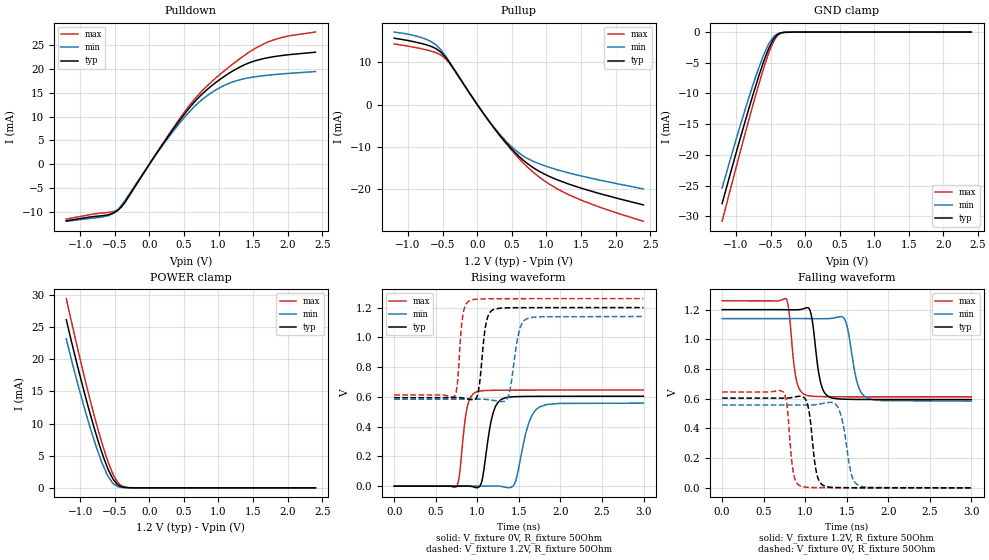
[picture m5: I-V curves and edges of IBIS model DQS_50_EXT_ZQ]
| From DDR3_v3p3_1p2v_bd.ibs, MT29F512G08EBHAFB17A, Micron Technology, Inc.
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| MODEL DQS_50_EXT_ZQ (50 Ohm Data Strobe I/O with no ODT, With ZQ Cal)
[Model]   DQS_50_EXT_ZQ
Model_type   I/O
Vinl = 450.000mV
Vinh = 750.000mV
Vmeas = 600.000mV
Vref = 600.000mV
Cref = 0.0pF
Rref = 50.000Ohm
|   typ   min   max
|C_comp   1.240pF   1.143pF   1.340pF
C_comp_pullup   0.6200pF   0.5715pF   0.6700pF
C_comp_pulldown   0.6200pF   0.5715pF   0.6700pF
[Model Spec]
| Input threshold voltage corners
Vinl   0.4500V   0.4200V   0.4800V
Vinh   0.7500V   0.7200V   0.7800V
| Measurement voltage corners
Vmeas   0.6000V   0.5700V   0.6300V
| Timing spec test load voltage corners
Vref   0.6000V   0.5700V   0.6300V
| Dynamic Overshoot Parameters from ONFI4 Specification
D_overshoot_ampl_h   0.80   NA   NA
D_overshoot_ampl_l   0.80   NA   NA
D_overshoot_area_h   0.38n   NA   NA
D_overshoot_area_l   0.38n   NA   NA
[Receiver Thresholds]
|Vth   =  0.600V
|Vth_min  =  0.5880V
|Vth_max  =  0.6120V
|Vinh_ac  =  0.150V
|Vinh_dc  =  0.100V
|Vinl_ac  = -0.150V
|Vinl_dc  = -0.100V
|Tslew_ac =  5.000ns |Not specified, so set to high value
|Threshold_sensitivity = 0.50
|Reference_supply Pullup_ref
Vcross_low   = 0.480V
Vcross_high  = 0.720V
Vdiff_ac   = 300mV
Vdiff_dc   = 200mV
Tdiffslew_ac = 10.000ns |Not specified, so set to high value
[Voltage Range]   1.2000V   1.1400V   1.2600V
[Pullup Reference]   1.2000V   1.1400V   1.2600V
| Junction Temperature (Ambient temp is 35C typ, 70C min, 0C max)
[Temperature Range]   50.0   85.0   0.0
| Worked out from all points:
|   slope of the pulldown table from 0 to 0.18 V, typ, clamps not added: 45.8 ohm
|   slope of the pullup table from 0 to 0.18 V, typ, clamps not added: 43.5 ohm
|   GND clamp passes 1 mA (typ) near -0.44 V on its own axis
|   POWER clamp passes 1 mA (typ) near -0.50 V on its own axis
|   falling waveform, V_fixture 1.2V, R_fixture 50Ohm: 20-80 % time 86ps typ, 108ps min, 73.2ps max; typ from 1.2 V to 0.594 V
|   rising waveform, V_fixture 0V, R_fixture 50Ohm: 20-80 % time 104ps typ, 140ps min, 77.8ps max; typ from 0 V to 0.604 V
|   rising waveform, V_fixture 1.2V, R_fixture 50Ohm: 20-80 % time 68.2ps typ, 90.4ps min, 52.9ps max; typ from 0.594 V to 1.2 V
|   falling waveform, V_fixture 0V, R_fixture 50Ohm: 20-80 % time 74.4ps typ, 97.1ps min, 60.8ps max; typ from 0.604 V to 0 V
[Pulldown]
|   Voltage   I(typ)   I(min)   I(max)
-1.2V     -11.9mA    -11.98mA   -11.52mA
-603.8mV  -10.66mA   -10.84mA   -10.13mA
-525.6mV  -10.31mA   -10.34mA   -9.968mA
-406.2mV  -8.981mA   -8.665mA   -8.998mA
130.4mV   2.867mA    2.72mA     2.942mA
446.2mV   9.375mA    8.794mA    9.732mA
719.8mV   14.13mA    13.06mA    14.77mA
966mV     17.24mA    15.66mA    18.2mA
1.324V    20.54mA    17.81mA    22.34mA
1.661V    22.23mA    18.62mA    25.35mA
1.997V    22.99mA    19.07mA    26.91mA
2.4V      23.54mA    19.47mA    27.77mA
[GND Clamp]
|   Voltage   I(typ)   I(min)   I(max)
-1.2V     -27.93mA   -25.37mA   -30.8mA
-976.8mV  -18.84mA   -16.69mA   -21.15mA
-838.6mV  -13.43mA   -11.57mA   -15.32mA
-681.3mV  -7.582mA   -6.181mA   -8.965mA
-603.8mV  -4.945mA   -3.844mA   -6.063mA
-525.6mV  -2.67mA    -1.913mA   -3.416mA
-460.8mV  -1.224mA   -852.9uA   -1.63mA
-447.6mV  -1.04mA    -637.3uA   -1.388mA
-406.2mV  -469uA     -373.7uA   -636.4uA
-355.8mV  -157.5uA   -119.8uA   -181.3uA
-118.9mV  -137.7nA   -5.032uA   0A
2.402V    0A         0A         0A
[Pullup]
|   Voltage   I(typ)   I(min)   I(max)
-1.2V     15.67mA    17.12mA    14.3mA
-682.4mV  13.83mA    15.02mA    12.7mA
-602.8mV  13.26mA    14.18mA    12.28mA
-461.6mV  11.28mA    11.54mA    10.86mA
-118.9mV  2.89mA     2.882mA    2.88mA
199.9mV   -4.575mA   -4.486mA   -4.619mA
456.9mV   -9.743mA   -9.33mA    -10.02mA
680.4mV   -13.32mA   -12.29mA   -14.03mA
970.6mV   -16.4mA    -14.42mA   -18mA
1.321V    -18.75mA   -16.11mA   -21.25mA
1.765V    -20.98mA   -17.8mA    -24.18mA
2.4V      -23.67mA   -19.89mA   -27.53mA
[POWER Clamp]
|   Voltage   I(typ)   I(min)   I(max)
-1.2V     26.15mA    23.18mA    29.43mA
-1.072V   20.45mA    17.71mA    23.36mA
-916.1mV  13.92mA    11.59mA    16.29mA
-796.8mV  9.308mA    7.386mA    11.27mA
-682.8mV  5.417mA    3.858mA    6.916mA
-603.8mV  3.107mA    1.935mA    4.308mA
-528mV    1.431mA    725uA      2.233mA
-461.6mV  525.6uA    247uA      933.2uA
-406.2mV  169.5uA    79.4uA     344uA
-355.8mV  81.44uA    14.39uA    117.3uA
-210.9mV  1.333uA    779.3nA    2.557uA
2.402V    0A         0A         0A
[Ramp]
R_load = 50
|   typ   min   max
dV/dt_r 3.6255E-01/1.0400E-10   3.3453E-01/1.3950E-10   3.8749E-01/7.7617E-11
dV/dt_f 3.6334E-01/8.5731E-11   3.3331E-01/1.0713E-10   3.8855E-01/7.2814E-11
[Falling Waveform]
V_fixture = 1.2V
V_fixture_min = 1.14V
V_fixture_max = 1.26V
R_fixture = 50Ohm
C_fixture = 0F
|   Time   V(typ)   V(min)   V(max)
0s        1.2V       1.14V      1.26V
776ps     1.2V       1.14V      1.269V
888ps     1.199V     1.14V      742.1mV
1.006ns   1.211V     1.14V      625.1mV
1.07ns    1.171V     1.14V      617.8mV
1.264ns   620.7mV    1.139V     613.8mV
1.472ns   597mV      1.139V     613mV
1.628ns   595.4mV    703.6mV    612.8mV
1.746ns   595mV      604.2mV    612.7mV
2.998ns   594.4mV    584.4mV    612.4mV
[Rising Waveform]
V_fixture = 0V
V_fixture_min = 0V
V_fixture_max = 0V
R_fixture = 50Ohm
C_fixture = 0F
|   Time   V(typ)   V(min)   V(max)
0s        103.7uV    217.2uV    28.95uV
748ps     212.7uV    98.54uV    -3.598mV
878ps     1.295mV    58.42uV    529.2mV
986ps     -10.23mV   40.97uV    632.6mV
1.19ns    491.8mV    1.196mV    643.9mV
1.286ns   581.6mV    -1.252mV   644.5mV
1.45ns    601.1mV    17.55mV    645.1mV
1.62ns    603.2mV    425.6mV    645.4mV
1.744ns   603.6mV    530.9mV    645.5mV
2.998ns   604.4mV    557.8mV    645.9mV
[Rising Waveform]
V_fixture = 1.2V
V_fixture_min = 1.14V
V_fixture_max = 1.26V
R_fixture = 50Ohm
C_fixture = 0F
|   Time   V(typ)   V(min)   V(max)
0s        594.4mV    584.4mV    612.4mV
724ps     594.5mV    584.2mV    601.8mV
826ps     592mV      584.1mV    1.149V
912ps     583.1mV    584.2mV    1.248V
1ns       605.7mV    584.4mV    1.256V
1.106ns   1.097V     582.8mV    1.258V
1.176ns   1.181V     577.6mV    1.259V
1.364ns   1.198V     591.9mV    1.259V
1.588ns   1.199V     1.123V     1.26V
2.998ns   1.2V       1.14V      1.26V
[Falling Waveform]
|Gnd
V_fixture = 0V
V_fixture_min = 0V
V_fixture_max = 0V
R_fixture = 50Ohm
C_fixture = 0F
|   Time   V(typ)   V(min)   V(max)
0s        604.3mV    557.7mV    645.8mV
734ps     603.9mV    557.9mV    647.2mV
858ps     610.3mV    558mV      98.93mV
944ps     617.3mV    557.6mV    11.85mV
1.028ns   560.7mV    557.2mV    3.434mV
1.122ns   142.1mV    559.8mV    1.798mV
1.204ns   20.4mV     567.7mV    1.279mV
1.408ns   1.656mV    524.7mV    675.9uV
1.63ns    746.6uV    20.04mV    399.8uV
2.998ns   84.92uV    178.6uV    19.94uV
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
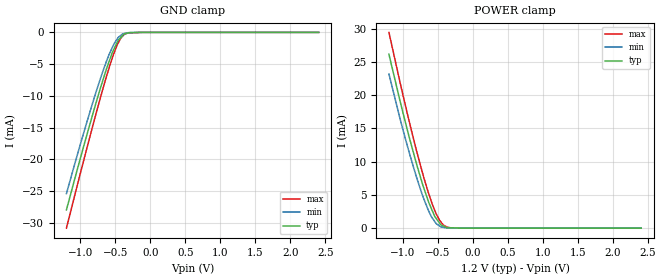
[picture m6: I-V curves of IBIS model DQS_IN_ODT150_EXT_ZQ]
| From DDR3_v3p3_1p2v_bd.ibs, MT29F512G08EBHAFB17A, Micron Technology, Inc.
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| MODEL DQS_IN_ODT150_EXT_ZQ (Data Strobe Input with 150ohm ODT, With ZQ Cal)
[Model]   DQS_IN_ODT150_EXT_ZQ
Model_type   Input
Vinl = 450.000mV
Vinh = 750.000mV
|   typ   min   max
|C_comp   1.207pF   1.100pF   1.320pF
C_comp_power_clamp   0.6035pF   0.5500pF   0.6600pF
C_comp_gnd_clamp   0.6035pF   0.5500pF   0.6600pF
| Note: C_comp changes when the ODT circuit is enabled.
[Model Spec]
| Input threshold voltage corners
Vinl   0.4500V   0.4200V   0.4800V
Vinh   0.7500V   0.7200V   0.7800V
| Dynamic Overshoot Parameters from ONFI4 Specification
D_overshoot_ampl_h   0.80   NA   NA
D_overshoot_ampl_l   0.80   NA   NA
D_overshoot_area_h   0.38n   NA   NA
D_overshoot_area_l   0.38n   NA   NA
[Receiver Thresholds]
|Vth   =  0.600V
|Vth_min  =  0.5880V
|Vth_max  =  0.6120V
|Vinh_ac  =  0.150V
|Vinh_dc  =  0.100V
|Vinl_ac  = -0.150V
|Vinl_dc  = -0.100V
|Tslew_ac =  5.000ns |Not specified, so set to high value
|Threshold_sensitivity = 0.50
|Reference_supply Power_clamp_ref
Vcross_low   = 0.480V
Vcross_high  = 0.720V
Vdiff_ac   = 300mV
Vdiff_dc   = 200mV
Tdiffslew_ac = 10.000ns |Not specified, so set to high value
[Voltage Range]   1.2000V   1.1400V   1.2600V
[POWER Clamp Reference]   1.2000V   1.1400V   1.2600V
| Junction Temperature (Ambient temp is 35C typ, 70C min, 0C max)
[Temperature Range]   50.0   85.0   0.0
[Add Submodel]
| Submodel Name   Mode
150ohm_ODT_EXT_ZQ   Non-Driving
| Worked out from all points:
|   GND clamp passes 1 mA (typ) near -0.44 V on its own axis
|   POWER clamp passes 1 mA (typ) near -0.49 V on its own axis
[GND Clamp]
|   Voltage   I(typ)   I(min)   I(max)
-1.2V     -27.93mA   -25.37mA   -30.8mA
-1.001V   -19.8mA    -17.6mA    -22.17mA
-831.8mV  -13.17mA   -11.32mA   -15.04mA
-715.2mV  -8.785mA   -7.288mA   -10.3mA
-639.3mV  -6.135mA   -4.883mA   -7.353mA
-544.8mV  -3.169mA   -2.381mA   -4.033mA
-475.5mV  -1.572mA   -1.055mA   -1.987mA
-423.8mV  -806.4uA   -480uA     -904.5uA
-372.2mV  -243.3uA   -177uA     -295.9uA
-320.5mV  -109.7uA   -55.24uA   -92.33uA
-118.9mV  0A         0A         -721.1nA
2.402V    0A         0A         0A
[POWER Clamp]
|   Voltage   I(typ)   I(min)   I(max)
-1.2V     26.15mA    23.18mA    29.43mA
-1.045V   19.27mA    16.59mA    22.09mA
-934.4mV  14.65mA    12.27mA    17.09mA
-728mV    6.895mA    5.162mA    8.593mA
-631.2mV  3.86mA     2.547mA    5.163mA
-590.1mV  2.845mA    1.66mA     3.888mA
-544.8mV  1.74mA     985.1uA    2.649mA
-475.5mV  736.6uA    310.2uA    1.155mA
-422.6mV  325.1uA    108.6uA    475.8uA
-320.5mV  34.77uA    7.16uA     55.39uA
-118.9mV  345.5nA    0A         220.3nA
2.402V    0A         0A         0A
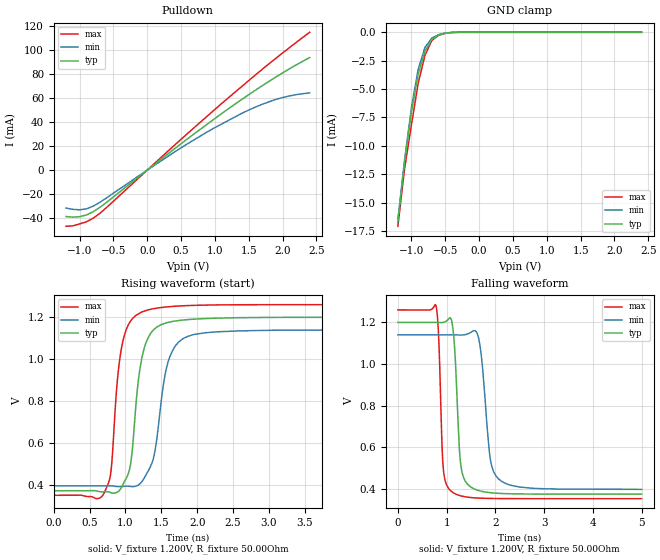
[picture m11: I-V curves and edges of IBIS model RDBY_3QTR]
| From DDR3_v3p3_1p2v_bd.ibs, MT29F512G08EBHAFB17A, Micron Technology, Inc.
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| MODEL RDBY_3QTR (3QTR-Drv RDBY Open-Drain Model)
[Model]   RDBY_3QTR
Model_type   Open_drain
Vmeas = 0.600V
Vref = 1.200V
Cref = 50.0pF
Rref = 1000.000Ohm
|   typ   min   max
|C_comp   2.216pF   2.116pF   2.317pF
C_comp_pulldown   2.2160pF   2.1160pF   2.3170pF
[Model Spec]
| Measurement voltage corners
Vmeas   0.600V   0.570V   0.630V
| Timing spec test load voltage corners
Vref   1.200V   1.140V   1.260V
[Voltage Range]   1.2000V   1.1400V   1.2600V
| Junction Temperature (Ambient temp is 35C typ, 70C min, 0C max)
[Temperature Range]   50.0   85.0   0.0
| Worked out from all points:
|   slope of the pulldown table from 0 to 0.18 V, typ, clamps not added: 22.6 ohm
|   GND clamp passes 1 mA (typ) near -0.73 V on its own axis
|   falling waveform, V_fixture 1.200V, R_fixture 50.00Ohm: 20-80 % time 104ps typ, 162ps min, 74.8ps max; typ from 1.2 V to 0.375 V
|   rising waveform, V_fixture 1.200V, R_fixture 50.00Ohm: 20-80 % time 162ps typ, 197ps min, 144ps max; typ from 0.375 V to 1.2 V
[Pulldown]
|   Voltage   I(typ)   I(min)   I(max)
-1.2V     -38.59mA   -31.52mA   -46.71mA
-1.1V     -39.08mA   -32.62mA   -46.36mA
-1V       -38.72mA   -33mA      -44.74mA
-900mV    -37.34mA   -32.24mA   -42.98mA
-700mV    -30.99mA   -26.77mA   -35.93mA
500mV     21.91mA    18.5mA     25.56mA
900mV     38.69mA    32.15mA    45.48mA
1.4V      58.82mA    47.25mA    69.63mA
1.7V      70.14mA    54.7mA     83.76mA
1.9V      77.3mA     58.71mA    92.84mA
2.1V      84.11mA    61.61mA    101.7mA
2.4V      93.5mA     64.15mA    114.5mA
[GND Clamp]
|   Voltage   I(typ)   I(min)   I(max)
-1.2V     -16.71mA   -16.48mA   -17.08mA
-1.1V     -11.43mA   -11.19mA   -11.97mA
-1V       -7.039mA   -6.642mA   -8.156mA
-900mV    -3.69mA    -3.252mA   -4.49mA
-800mV    -1.665mA   -1.331mA   -2.029mA
-700mV    -665.8uA   -519.3uA   -743.3uA
-600mV    -239.8uA   -203.8uA   -263uA
-500mV    -79.03uA   -66.37uA   -92.32uA
-300mV    -733.9nA   0A         -2.834uA
2.4V      0A         0A         0A
[POWER Clamp]
|   Voltage   I(typ)   I(min)   I(max)
-1.2V     0A         0A         0A
0V        0A         0A         0A
2.4V      0A         0A         0A
[Ramp]
R_load = 50.00Ohm
|   typ   min   max
dV/dt_r   495.077mV/162.175ps 445.216mV/196.849ps 544.116mV/143.777ps
dV/dt_f   495.077mV/104.370ps 445.216mV/162.035ps 544.116mV/74.770ps
[Falling Waveform]
V_fixture = 1.200V
V_fixture_min = 1.140V
V_fixture_max = 1.260V
R_fixture = 50.00Ohm
|   Time   V(typ)   V(min)   V(max)
0s        1.2V       1.14V      1.26V
780ps     1.2V       1.14V      1.282V
930ps     1.2V       1.14V      504.8mV
1.1ns     1.21V      1.14V      387.8mV
1.28ns    537.8mV    1.139V     367.6mV
1.44ns    420mV      1.145V     360.2mV
1.66ns    392.2mV    1.121V     356.1mV
1.89ns    382.3mV    554.6mV    354.5mV
2.06ns    379mV      449.3mV    354mV
5ns       375mV      398.1mV    353.2mV
[Rising Waveform]
V_fixture = 1.200V
V_fixture_min = 1.140V
V_fixture_max = 1.260V
R_fixture = 50.00Ohm
|   Time   V(typ)   V(min)   V(max)
0s        375mV      398.1mV    353.2mV
700ps     369.7mV    398.2mV    362.9mV
800ps     365.6mV    398.3mV    474.9mV
920ps     378.5mV    394.5mV    1.002V
1.05ns    467.7mV    396mV      1.171V
1.22ns    990.8mV    414.7mV    1.224V
1.4ns     1.143V     544.3mV    1.241V
1.59ns    1.175V     982.5mV    1.25V
1.82ns    1.188V     1.102V     1.255V
5ns       1.2V       1.14V      1.26V
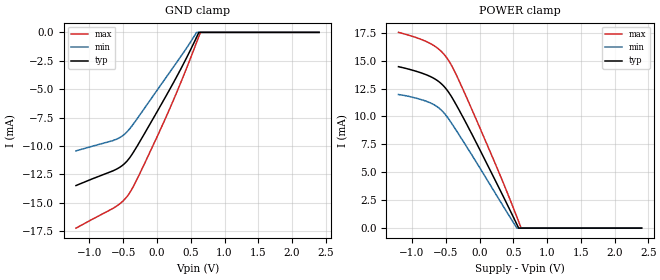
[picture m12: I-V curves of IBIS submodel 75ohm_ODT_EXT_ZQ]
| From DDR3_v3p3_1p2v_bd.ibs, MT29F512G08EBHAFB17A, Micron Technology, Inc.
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| SUBMODEL 75ohm_ODT_EXT_ZQ
[Submodel]   75ohm_ODT_EXT_ZQ
Submodel_type  Dynamic_clamp
[GND Clamp]
|   Voltage   I(typ)   I(min)   I(max)
-1.2V     -13.48mA   -10.42mA   -17.22mA
-616.5mV  -12.08mA   -9.439mA   -15.35mA
-506mV    -11.67mA   -9.078mA   -14.85mA
-403.5mV  -11.02mA   -8.474mA   -14.1mA
-334mV    -10.4mA    -7.93mA    -13.37mA
-233.5mV  -9.395mA   -7.084mA   -12.15mA
130.5mV   -5.628mA   -3.997mA   -7.491mA
322.5mV   -3.555mA   -2.375mA   -4.84mA
535mV     -1.062mA   -488.1uA   -1.671mA
620mV     0A         NA         NA
2.4V      0A         0A         0A
[POWER Clamp]
|   Voltage   I(typ)   I(min)   I(max)
-1.2V     14.46mA    11.96mA    17.53mA
-891mV    13.95mA    11.56mA    16.96mA
-701.5mV  13.49mA    11.14mA    16.44mA
-574.5mV  12.98mA    10.62mA    15.87mA
-461mV    12.2mA     9.811mA    15.04mA
-349mV    11.08mA    8.793mA    13.79mA
-99mV     8.25mA     6.411mA    10.43mA
271mV     3.818mA    2.754mA    5.23mA
488mV     1.149mA    630.5uA    2.009mA
580mV     0A         NA         NA
2.4V      0A         0A         0A
